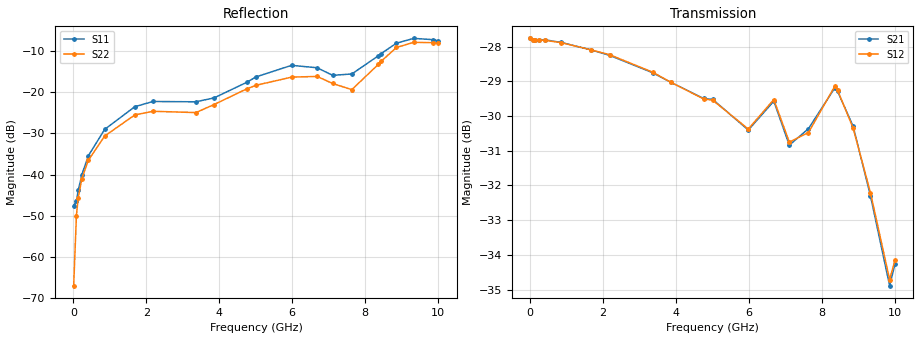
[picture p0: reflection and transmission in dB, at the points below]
! Device ID: PE43705
! Serial: 1
! Insertion: A
! Impedance: 50 ohm
! Temp: 25C
! VDD: 3.400V
! Attenuation Step: 26.75dB
#  Hz  S  RI  R  50
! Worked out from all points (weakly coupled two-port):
!   401 points, 10 MHz to 10.01 GHz, reference 50 ohm
!   highest |S21| = -27.76 dB at 10 MHz (marker M1); lowest = -34.9 dB at 9.86 GHz (marker M2)
!   lowest |S11| = -47.7 dB at 10 MHz (marker M3), VSWR 1.01, Z = 49.6 + j0.0398 ohm
!   |S11| at or under -10 dB: start of sweep to 8.523 GHz
!   |S22| runs from -67.0 to -7.8 dB; largest |S21 - S12| = 0.00079
!   S11 on the Smith chart (normalised r, x): 10 MHz: 0.99, +0.00; 4.76 GHz: 0.79, +0.12; 8.435 GHz: 0.79, +0.50; 9.335 GHz: 0.51, +0.53; 10.01 GHz: 0.46, +0.31
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1e7  -0.00408 0.000401  0.0409 -0.000149  0.0409 -0.000146  -0.000151 0.00042
8.5e7  -0.00379 0.00297  0.0407 -0.000986  0.0407 -0.000904  0.000367 0.00315
1.35e8  -0.0039 0.00507  0.0407 -0.00146  0.0407 -0.00143  0.000264 0.00524
2.35e8  -0.00505 0.00858  0.0406 -0.00252  0.0406 -0.00246  -0.000502 0.0089
4.1e8  -0.00872 0.0144  0.0405 -0.00411  0.0404 -0.0043  -0.00368 0.0144
8.6e8  -0.0279 0.0217  0.0394 -0.00868  0.0394 -0.0086  -0.0196 0.0218
1.685e9  -0.066 0.00874  0.036 -0.0159  0.036 -0.0159  -0.0516 0.0118
2.185e9  -0.0768 -0.00673  0.0332 -0.0198  0.0333 -0.0198  -0.0586 0.000778
3.36e9  -0.0762 -0.00559  0.0251 -0.0265  0.0252 -0.0265  -0.0563 0.00506
3.86e9  -0.0831 0.0189  0.0216 -0.028  0.0216 -0.028  -0.0678 0.0203
4.76e9  -0.1109 0.0717  0.0159 -0.0295  0.0158 -0.0295  -0.0962 0.0533
5.01e9  -0.1265 0.0867  0.0147 -0.03  0.0145 -0.03  -0.1055 0.0598
5.985e9  -0.181 0.11  0.00837 -0.029  0.00839 -0.0291  -0.1319 0.0762
6.685e9  -0.173 0.0961  0.00582 -0.0327  0.00572 -0.0329  -0.1382 0.0708
7.11e9  -0.1386 0.0803  0.000555 -0.0287  0.000521 -0.029  -0.1048 0.0726
7.635e9  -0.0909 0.1393  0.00117 -0.0303  0.00135 -0.0299  -0.0546 0.0924
8.36e9  -0.0327 0.2741  -0.00796 -0.0338  -0.008 -0.034  -0.0335 0.2145
8.435e9  -0.0353 0.2913  -0.00937 -0.033  -0.00944 -0.0331  -0.0363 0.2333
8.86e9  -0.0868 0.3841  -0.0145 -0.0269  -0.0141 -0.0269  -0.0941 0.3364
9.335e9  -0.1817 0.4121  -0.0136 -0.0201  -0.0139 -0.0202  -0.1923 0.3547
9.86e9  -0.2917 0.3216  -0.00625 -0.0169  -0.00651 -0.0172  -0.3147 0.245
1.001e10  -0.316 0.2757  -0.00377 -0.019  -0.00403 -0.0192  -0.3445 0.1858
